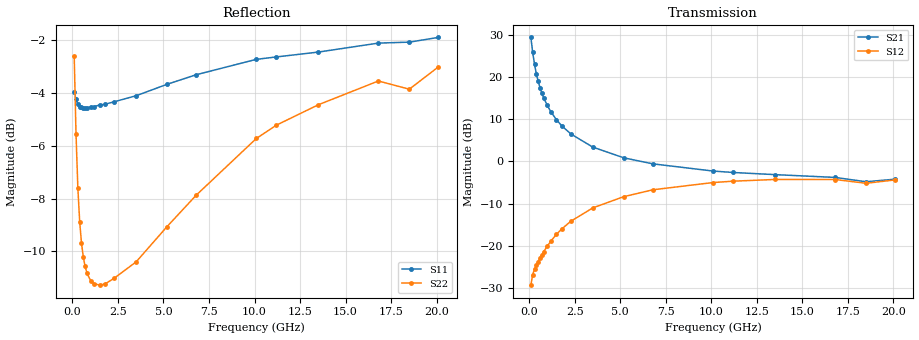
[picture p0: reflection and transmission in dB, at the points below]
!  Infineon Technologies AG
! BFR380L3 , PF131585-7, No.6, Th 09.10.01, soldered on pcb-board, measured with PP GSG850
!  Vce=0.5 V,  Ic=15.0 mA
! Common Emitter S-Parameters:  15. November 2001
#  GHz  S  MA  R  50
! f  S11  S21  S12  S22
! GHz  Mag  Ang  Mag  Ang  Mag  Ang  Mag  Ang
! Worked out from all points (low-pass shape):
!   201 points, 100 MHz to 20.1 GHz, reference 50 ohm
!   highest |S21| = 29.37 dB at 100 MHz (marker M1); lowest = -4.8 dB at 18.5 GHz (marker M2)
!   |S21| within 3 dB of the highest: start of sweep to 184.5 MHz
!   lowest |S11| = -4.6 dB at 700 MHz (marker M3), VSWR 3.89, Z = 13 - j4.49 ohm
!   |S11| at or under -10 dB: nowhere
!   |S22| runs from -11.3 to -2.6 dB; largest |S21 - S12| = 29
!   S11 on the Smith chart (normalised r, x): 100 MHz: 0.53, -1.09; 300 MHz: 0.28, -0.36; 1.5 GHz: 0.25, +0.09; 5.2 GHz: 0.28, +0.58; 11.2 GHz: 0.44, +1.34; 20.1 GHz: 0.91, +2.58
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0.1  0.6326 -77.7  29.43 137.9  0.03432 57.1  0.7399 -53.6
0.2  0.6133 -117.9  19.55 117.3  0.04579 48.1  0.5275 -84.4
0.3  0.6002 -137.6  14.12 107.0  0.05304 46.4  0.4173 -103.3
0.4  0.5937 -150.1  10.95 100.6  0.05906 47.4  0.36 -116.7
0.5  0.5925 -158.0  8.904 95.8  0.06486 49.4  0.3279 -126.8
0.6  0.5911 -164.2  7.493 92.3  0.0716 51.2  0.3083 -134.5
0.7  0.5907 -169.0  6.474 89.1  0.07823 52.8  0.296 -140.8
0.8  0.5911 -172.9  5.695 86.4  0.08516 54.3  0.2875 -146.0
1  0.5934 -179.5  4.601 81.8  0.09933 56.3  0.2783 -154.0
1.2  0.5945 175.1  3.865 77.7  0.114 57.4  0.2745 -160.0
1.5  0.5987 168.6  3.128 72.2  0.1365 58.0  0.2729 -166.9
1.8  0.6006 162.8  2.637 67.2  0.1591 57.8  0.2744 -172.3
2.3  0.6072 154.0  2.112 59.4  0.1962 56.1  0.2813 -179.6
3.5  0.6233 136.4  1.478 43.3  0.2818 49.3  0.302 167.4
5.2  0.6552 116.4  1.104 24.8  0.3827 37.2  0.3523 151.9
6.8  0.6831 99.9  0.9361 11.3  0.4618 26.4  0.404 136.4
10.1  0.7305 76.0  0.7698 -8.3  0.5624 5.7  0.5173 111.8
11.2  0.7382 69.9  0.74 -13.8  0.5837 -0.9  0.5482 104.0
13.5  0.754 59.3  0.6979 -23.7  0.6116 -13.4  0.5991 89.1
16.8  0.7841 47.5  0.647 -35.1  0.611 -27.9  0.6647 71.4
18.5  0.7874 45.3  0.575 -42.2  0.5515 -35.9  0.6413 66.9
20.1  0.8039 38.4  0.6164 -45.6  0.6038 -40.5  0.707 57.2
